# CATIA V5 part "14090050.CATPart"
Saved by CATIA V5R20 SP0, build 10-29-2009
Part number: 14090050
Definition: NONE
Nomenclature: 14090050
Source: Unknown
Description: 14090050
Bounding box of the stored display mesh (mm): x -25 to 100, y -59 to 49.1, z -49.1 to 49.1
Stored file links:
  C:\Users\Utente\Desktop\IO LAVORO\3D X SITO CF\X SITO\PLASTICA\RF2\14090050.CATPart

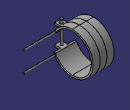
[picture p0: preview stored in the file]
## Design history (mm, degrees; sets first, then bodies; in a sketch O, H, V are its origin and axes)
Body1 "14090050" (main body)
  Solid1: solid without history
